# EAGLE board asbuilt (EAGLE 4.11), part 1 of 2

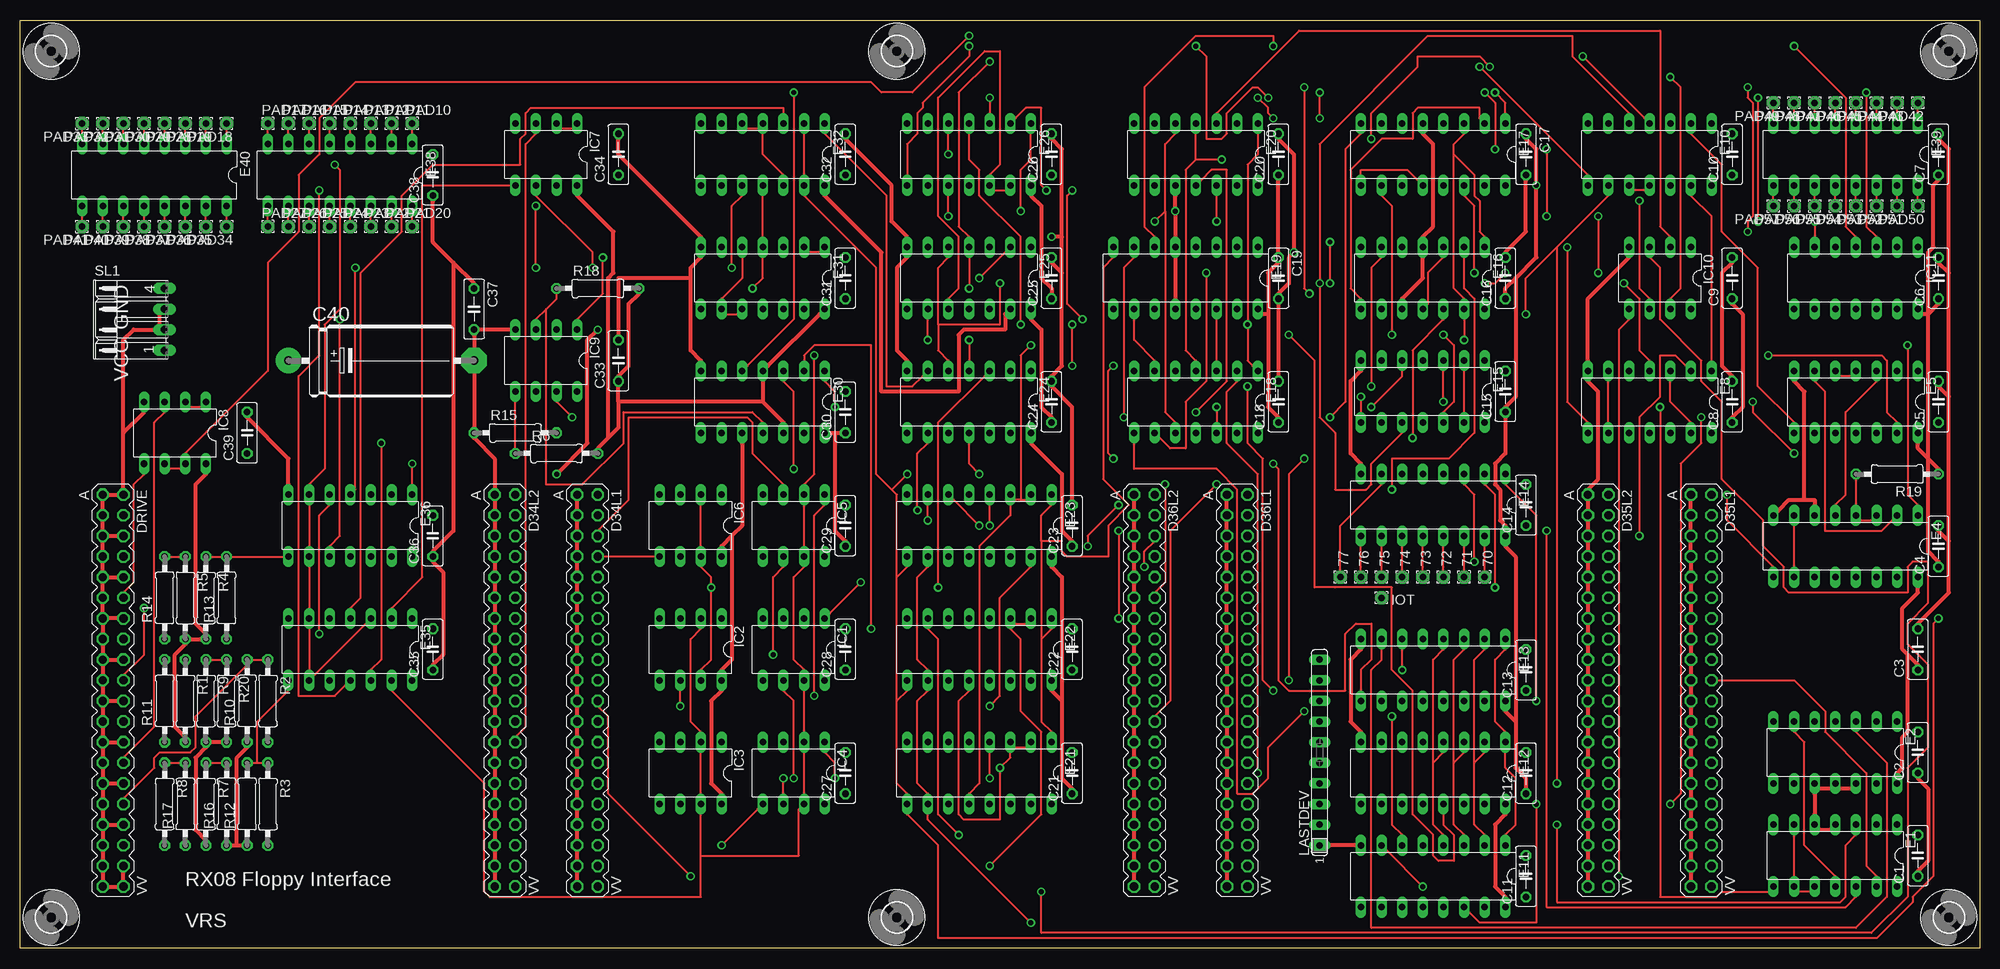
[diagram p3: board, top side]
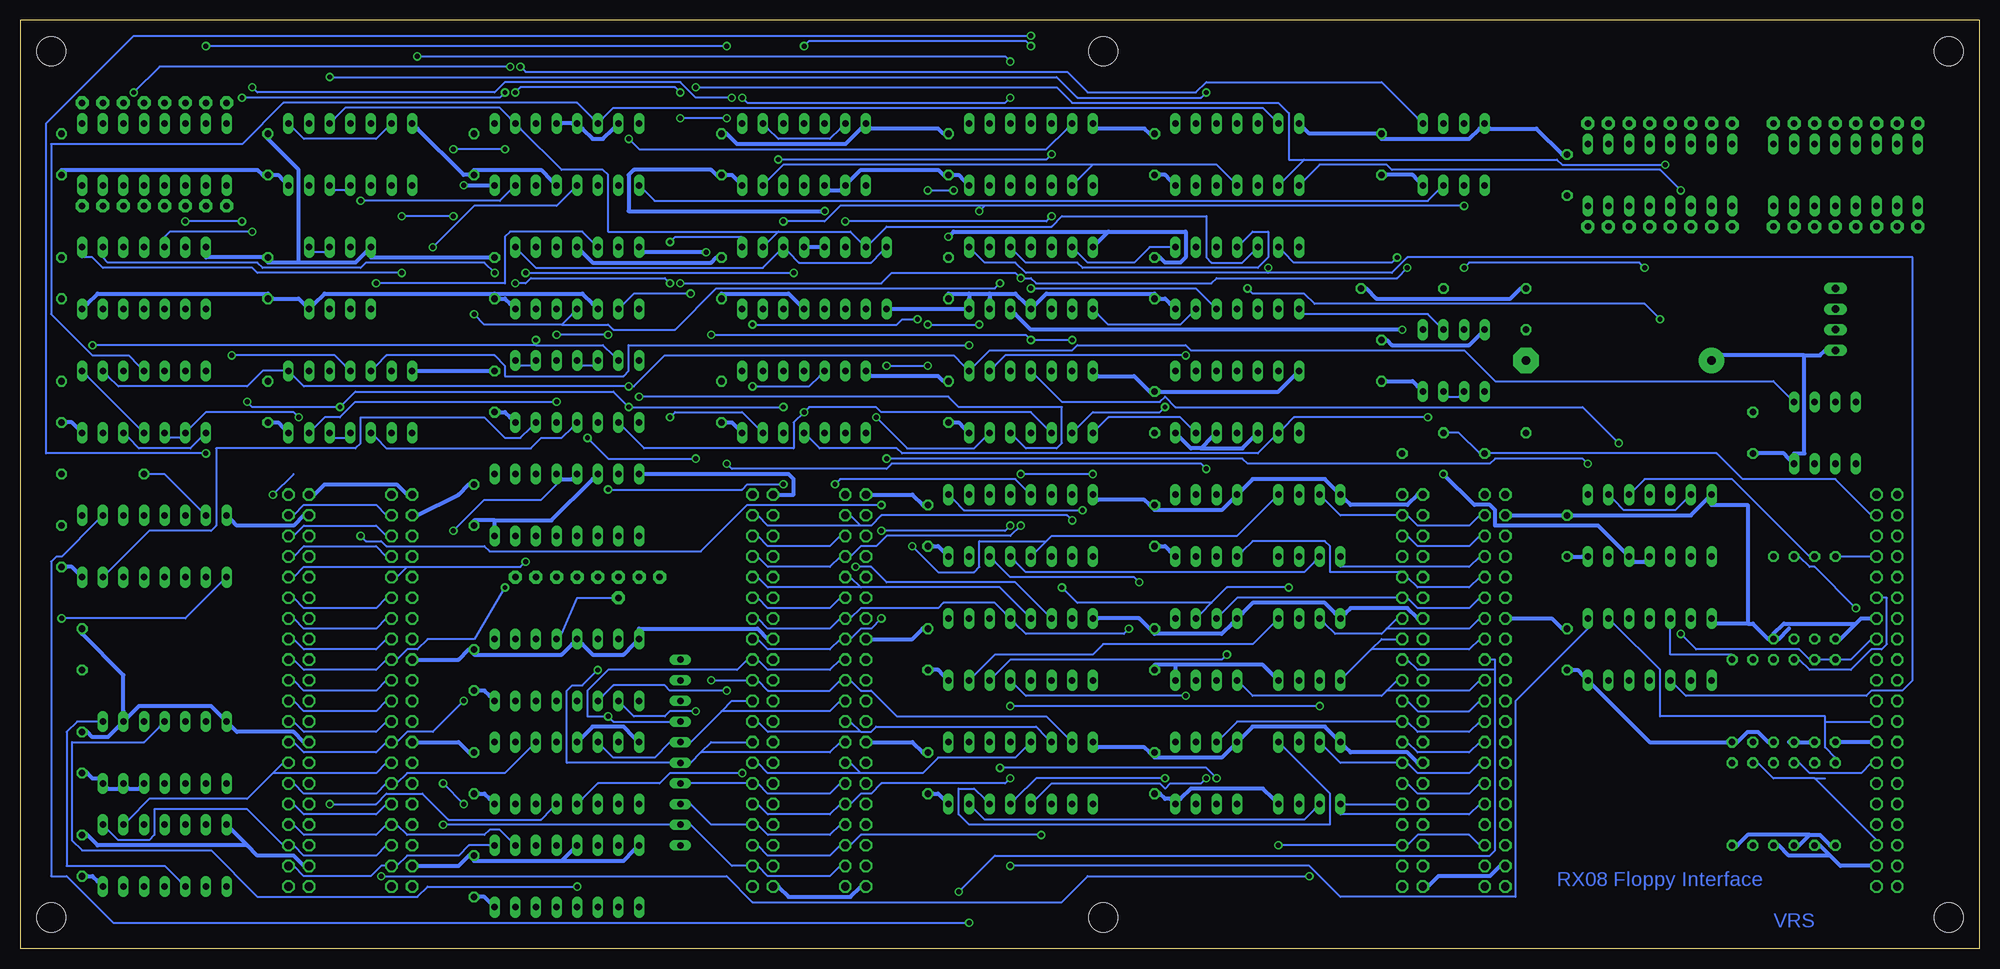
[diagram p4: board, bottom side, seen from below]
Size 241.3 x 114.3 mm. Coordinates in mm from the lower left corner, seen from the top.
Outline: 0,0 0,114.3 241.3,114.3 241.3,0 0,0
Copper layers (1*16): Top 0.035mm / dielectric 1.5mm / Bottom 0.035mm
Design rules "olimex10mil": minimum track width 10mil, minimum drill 24mil, track to track 10mil, track to pad 10mil, pad to pad 10mil, via to via 10mil, smd to smd 10mil, copper to edge 25mil, drill to drill 10mil, minimum pad ring 10mil, minimum via ring 8mil, stop-mask expansion 0mil, vias tented up to drill 0mil, thermal gap 10mil
Net classes: 1 supply: width 0.508 mm

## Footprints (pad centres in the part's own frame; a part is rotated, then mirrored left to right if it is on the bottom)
1,6/0,8 = drill 0.813 pad 1.6 octagon: 1 0,0
C050-025X075 = drill 0.813 octagon: 1 -2.54,0; 2 2.54,0
E22-9 = drill 1.016 pad 3.15 round: + -11.43,0 | drill 1.016 pad 3.15 octagon: - 11.43,0
DEC40PIN = drill 1.016 octagon: A -24.13,-1.27; AA 3.81,-1.27; B -24.13,1.27; BB 3.81,1.27; C -21.59,-1.27; CC 6.35,-1.27; D -21.59,1.27; DD 6.35,1.27; E -19.05,-1.27; EE 8.89,-1.27; F -19.05,1.27; FF 8.89,1.27; H -16.51,-1.27; HH 11.43,-1.27; J -16.51,1.27; JJ 11.43,1.27; K -13.97,-1.27; KK 13.97,-1.27; L -13.97,1.27; LL 13.97,1.27; M -11.43,-1.27; MM 16.51,-1.27; N -11.43,1.27; NN 16.51,1.27; P -8.89,-1.27; PP 19.05,-1.27; R -8.89,1.27; RR 19.05,1.27; S -6.35,-1.27; SS 21.59,-1.27; T -6.35,1.27; TT 21.59,1.27; U -3.81,-1.27; UU 24.13,-1.27; V -3.81,1.27; VV 24.13,1.27; W -1.27,-1.27; X -1.27,1.27; Y 1.27,-1.27; Z 1.27,1.27
DIL14 = drill 0.813 long: 1 -7.62,-3.81; 2 -5.08,-3.81; 3 -2.54,-3.81; 4 0,-3.81; 5 2.54,-3.81; 6 5.08,-3.81; 7 7.62,-3.81; 8 7.62,3.81; 9 5.08,3.81; 10 2.54,3.81; 11 0,3.81; 12 -2.54,3.81; 13 -5.08,3.81; 14 -7.62,3.81
DIL16 = drill 0.813 long: 1 -8.89,-3.81; 2 -6.35,-3.81; 3 -3.81,-3.81; 4 -1.27,-3.81; 5 1.27,-3.81; 6 3.81,-3.81; 7 6.35,-3.81; 8 8.89,-3.81; 9 8.89,3.81; 10 6.35,3.81; 11 3.81,3.81; 12 1.27,3.81; 13 -1.27,3.81; 14 -3.81,3.81; 15 -6.35,3.81; 16 -8.89,3.81
DIL08 = drill 0.813 long: 1 -3.81,-3.81; 2 -1.27,-3.81; 3 1.27,-3.81; 4 3.81,-3.81; 5 3.81,3.81; 6 1.27,3.81; 7 -1.27,3.81; 8 -3.81,3.81
SIL10 = drill 0.813 long: 1 -11.43,0; 2 -8.89,0; 3 -6.35,0; 4 -3.81,0; 5 -1.27,0; 6 1.27,0; 7 3.81,0; 8 6.35,0; 9 8.89,0; 10 11.43,0
0207/10 = drill 0.813 octagon: 1 -5.08,0; 2 5.08,0
04PA = drill 0.914 long: 1 -3.81,0; 2 -1.27,0; 3 1.27,0; 4 3.81,0
3,6 = hole 3.6: 0,0

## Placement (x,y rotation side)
70  [1,6/0,8]  180.34,45.72 270 top
71  [1,6/0,8]  177.8,45.72 270 top
72  [1,6/0,8]  175.26,45.72 270 top
73  [1,6/0,8]  172.72,45.72 270 top
74  [1,6/0,8]  170.18,45.72 270 top
75  [1,6/0,8]  167.64,45.72 270 top
76  [1,6/0,8]  165.1,45.72 270 top
77  [1,6/0,8]  162.56,45.72 270 top
C1  0.1  [C050-025X075]  233.68,11.43 90 top
C2  0.1  [C050-025X075]  233.68,24.13 90 top
C3  0.1  [C050-025X075]  233.68,36.83 90 top
C4  0.1  [C050-025X075]  236.22,49.53 90 top
C5  0.1  [C050-025X075]  236.22,67.31 90 top
C6  0.1  [C050-025X075]  236.22,82.55 90 top
C7  0.1  [C050-025X075]  236.22,97.79 90 top
C8  0.1  [C050-025X075]  210.82,67.31 90 top
C9  0.1  [C050-025X075]  210.82,82.55 90 top
C10  0.1  [C050-025X075]  210.82,97.79 90 top
C11  0.1  [C050-025X075]  185.42,8.89 90 top
C12  0.1  [C050-025X075]  185.42,21.59 90 top
C13  0.1  [C050-025X075]  185.42,34.29 90 top
C14  0.1  [C050-025X075]  185.42,54.61 90 top
C15  0.1  [C050-025X075]  182.88,68.58 90 top
C16  0.1  [C050-025X075]  182.88,82.55 90 top
C17  0.1  [C050-025X075]  185.42,97.79 270 top
C18  0.1  [C050-025X075]  154.94,67.31 90 top
C19  0.1  [C050-025X075]  154.94,82.55 270 top
C20  0.1  [C050-025X075]  154.94,97.79 90 top
C21  0.1  [C050-025X075]  129.54,21.59 90 top
C22  0.1  [C050-025X075]  129.54,36.83 90 top
C23  0.1  [C050-025X075]  129.54,52.07 90 top
C24  0.1  [C050-025X075]  127,67.31 90 top
C25  0.1  [C050-025X075]  127,82.55 90 top
C26  0.1  [C050-025X075]  127,97.79 90 top
C27  0.1  [C050-025X075]  101.6,21.59 90 top
C28  0.1  [C050-025X075]  101.6,36.83 90 top
C29  0.1  [C050-025X075]  101.6,52.07 90 top
C30  0.1  [C050-025X075]  101.6,66.04 90 top
C31  0.1  [C050-025X075]  101.6,82.55 90 top
C32  0.1  [C050-025X075]  101.6,97.79 90 top
C33  0.1  [C050-025X075]  73.66,72.39 90 top
C34  0.1  [C050-025X075]  73.66,97.79 90 top
C35  0.1  [C050-025X075]  50.8,36.83 90 top
C36  0.1  [C050-025X075]  50.8,50.8 90 top
C37  0.1  [C050-025X075]  55.88,78.74 270 top
C38  0.1  [C050-025X075]  50.8,95.25 90 top
C39  0.1  [C050-025X075]  27.94,63.5 90 top
C40  100uf  [E22-9]  44.45,72.39 0 top
D34L1  [DEC40PIN]  69.85,31.75 270 top
D34L2  [DEC40PIN]  59.69,31.75 270 top
D35L1  [DEC40PIN]  207.01,31.75 270 top
D35L2  [DEC40PIN]  194.31,31.75 270 top
D36L1  [DEC40PIN]  149.86,31.75 270 top
D36L2  [DEC40PIN]  138.43,31.75 270 top
DRIVE  [DEC40PIN]  11.43,31.75 270 top
E1  74LS10N  [DIL14]  223.52,11.43 180 top
E2  74LS74N  [DIL14]  223.52,24.13 180 top
E4  74LS161N  [DIL16]  224.79,49.53 180 top
E5  74LS00N  [DIL14]  226.06,67.31 180 top
E8  74LS10N  [DIL14]  200.66,67.31 180 top
E10  74LS10N  [DIL14]  200.66,97.79 180 top
E11  74LS138N  [DIL16]  173.99,8.89 180 top
E12  74LS138N  [DIL16]  173.99,21.59 180 top
E13  74LS138N  [DIL16]  173.99,34.29 180 top
E14  74LS138N  [DIL16]  173.99,54.61 180 top
E15  74LS00N  [DIL14]  172.72,68.58 180 top
E16  74LS74N  [DIL14]  172.72,82.55 180 top
E17  74LS76N  [DIL16]  173.99,97.79 180 top
E18  74LS02N  [DIL14]  144.78,67.31 180 top
E19  74LS76N  [DIL16]  143.51,82.55 180 top
E20  74HCT32N  [DIL14]  144.78,97.79 180 top
E21  74LS195N  [DIL16]  118.11,21.59 180 top
E22  74LS195N  [DIL16]  118.11,36.83 180 top
E23  74LS195N  [DIL16]  118.11,52.07 180 top
E24  74LS08N  [DIL14]  116.84,67.31 180 top
E25  74LS04N  [DIL14]  116.84,82.55 180 top
E26  74LS86N  [DIL14]  116.84,97.79 180 top
E30  74LS74N  [DIL14]  91.44,67.31 180 top
E31  74LS20N  [DIL14]  91.44,82.55 180 top
E32  74LS27N  [DIL14]  91.44,97.79 180 top
E35  74HCT02N  [DIL14]  40.64,36.83 180 top
E36  74HCT02N  [DIL14]  40.64,52.07 180 top
E38  SPARE  [DIL16]  39.37,95.25 180 top
E39  SPARE  [DIL16]  224.79,97.79 180 top
E40  SPARE  [DIL16]  16.51,95.25 180 top
IC1  DS75452N  [DIL08]  95.25,36.83 180 top
IC2  DS75452N  [DIL08]  82.55,36.83 180 top
IC3  DS75452N  [DIL08]  82.55,21.59 180 top
IC4  DS75452N  [DIL08]  95.25,21.59 180 top
IC5  DS75452N  [DIL08]  95.25,52.07 180 top
IC6  DS75452N  [DIL08]  82.55,52.07 180 top
IC7  DS75452N  [DIL08]  64.77,97.79 180 top
IC8  DS75452N  [DIL08]  19.05,63.5 180 top
IC9  DS75452N  [DIL08]  64.77,72.39 180 top
IC10  DS75452N  [DIL08]  201.93,82.55 180 top
IC11  74LS04N  [DIL14]  226.06,82.55 180 top
IOT  [1,6/0,8]  167.64,43.18 270 top
LASTDEV  100  [SIL10]  160.02,24.13 90 top
PAD10  [1,6/0,8]  48.26,101.6 0 top
PAD11  [1,6/0,8]  45.72,101.6 0 top
PAD12  [1,6/0,8]  43.18,101.6 0 top
PAD13  [1,6/0,8]  40.64,101.6 0 top
PAD14  [1,6/0,8]  38.1,101.6 0 top
PAD15  [1,6/0,8]  35.56,101.6 0 top
PAD16  [1,6/0,8]  33.02,101.6 0 top
PAD17  [1,6/0,8]  30.48,101.6 0 top
PAD18  [1,6/0,8]  25.4,101.6 180 top
PAD19  [1,6/0,8]  22.86,101.6 180 top
PAD20  [1,6/0,8]  48.26,88.9 0 top
PAD21  [1,6/0,8]  45.72,88.9 0 top
PAD22  [1,6/0,8]  43.18,88.9 0 top
PAD23  [1,6/0,8]  40.64,88.9 0 top
PAD24  [1,6/0,8]  38.1,88.9 0 top
PAD25  [1,6/0,8]  35.56,88.9 0 top
PAD26  [1,6/0,8]  33.02,88.9 0 top
PAD27  [1,6/0,8]  30.48,88.9 0 top
PAD28  [1,6/0,8]  20.32,101.6 180 top
PAD29  [1,6/0,8]  17.78,101.6 180 top
PAD30  [1,6/0,8]  15.24,101.6 180 top
PAD31  [1,6/0,8]  12.7,101.6 180 top
PAD32  [1,6/0,8]  10.16,101.6 180 top
PAD33  [1,6/0,8]  7.62,101.6 180 top
PAD34  [1,6/0,8]  25.4,88.9 180 top
PAD35  [1,6/0,8]  22.86,88.9 180 top
PAD36  [1,6/0,8]  20.32,88.9 180 top
PAD37  [1,6/0,8]  17.78,88.9 180 top
PAD38  [1,6/0,8]  15.24,88.9 180 top
PAD39  [1,6/0,8]  12.7,88.9 180 top
PAD40  [1,6/0,8]  10.16,88.9 180 top
PAD41  [1,6/0,8]  7.62,88.9 180 top
PAD42  [1,6/0,8]  233.68,104.14 180 top
PAD43  [1,6/0,8]  231.14,104.14 180 top
PAD44  [1,6/0,8]  228.6,104.14 180 top
PAD45  [1,6/0,8]  226.06,104.14 180 top
PAD46  [1,6/0,8]  223.52,104.14 180 top
PAD47  [1,6/0,8]  220.98,104.14 180 top
PAD48  [1,6/0,8]  218.44,104.14 180 top
PAD49  [1,6/0,8]  215.9,104.14 180 top
PAD50  [1,6/0,8]  233.68,91.44 180 top
PAD51  [1,6/0,8]  231.14,91.44 180 top
PAD52  [1,6/0,8]  228.6,91.44 180 top
PAD53  [1,6/0,8]  226.06,91.44 180 top
PAD54  [1,6/0,8]  223.52,91.44 180 top
PAD55  [1,6/0,8]  220.98,91.44 180 top
PAD56  [1,6/0,8]  218.44,91.44 180 top
PAD57  [1,6/0,8]  215.9,91.44 180 top
R1  180  [0207/10]  20.32,30.48 270 top
R2  180  [0207/10]  30.48,30.48 270 top
R3  180  [0207/10]  30.48,17.78 270 top
R4  180  [0207/10]  22.86,43.18 270 top
R5  180  [0207/10]  20.32,43.18 270 top
R6  180  [0207/10]  66.04,60.96 0 top
R7  180  [0207/10]  22.86,17.78 270 top
R8  180  [0207/10]  17.78,17.78 270 top
R9  390  [0207/10]  22.86,30.48 270 top
R10  390  [0207/10]  27.94,30.48 90 top
R11  390  [0207/10]  17.78,30.48 90 top
R12  390  [0207/10]  27.94,17.78 90 top
R13  390  [0207/10]  25.4,43.18 90 top
R14  390  [0207/10]  17.78,43.18 90 top
R15  390  [0207/10]  60.96,63.5 0 top
R16  390  [0207/10]  25.4,17.78 90 top
R17  390  [0207/10]  20.32,17.78 90 top
R18  10K  [0207/10]  71.12,81.28 0 top
R19  10K  [0207/10]  231.14,58.42 180 top
R20  180  [0207/10]  25.4,30.48 270 top
SL1  [04PA]  17.78,77.47 90 top
U$1  [3,6]  237.49,3.81 0 top
U$2  [3,6]  237.49,110.49 0 top
U$3  [3,6]  3.81,110.49 0 top
U$4  [3,6]  3.81,3.81 0 top
U$5  [3,6]  107.95,110.49 0 top
U$6  [3,6]  107.95,3.81 0 top

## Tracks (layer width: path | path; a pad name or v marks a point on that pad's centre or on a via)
8/12  (via drill 0.61)
  Top 0.254: v197.49,81.92 199.39,80.01 199.39,73.66 200.66,72.39 E8.4 | v215.26,73.03 229.24,73.03 229.87,72.39 229.87,66.04 231.14,64.77 E5.13
  Bottom 0.254: v197.49,81.92 181.61,81.92 181.61,87.63 180.97,88.27 172.09,88.27 170.81,87 E16.5 | v215.26,73.03 202.56,73.03 201.29,71.75 E8.4
8/12\  (via drill 0.61)
  Top 0.254: v166.37,69.22 166.37,83.82 167.64,85.09 E16.6 | E10.13 205.74,92.71 208.28,90.17 208.28,72.39 E8.1 | IC8.2 20.95,66.67 22.23,66.67 IC8.1
  Bottom 0.254: E5.2 230.5,70.48 229.24,69.22 213.36,69.22 211.46,71.12 208.91,71.12 E8.1 207.65,70.48 206.38,69.22 v166.37,69.22 165.74,69.22 161.93,73.03 126.36,73.03 125.09,71.75 E24.1 123.83,71.75 121.92,73.66 111.76,73.66 111.12,74.3 97.79,74.3 97.16,73.66 63.5,73.66 59.69,69.85 25.4,69.85 23.5,67.94 IC8.1
ACB00\
  Bottom 0.254: IC6.3 80.64,55.24 78.74,53.34 71.75,53.34 D34L1.D 70.48,53.34 69.22,52.07 62.87,52.07 61.59,53.34 D34L2.D
ACB01\
  Top 0.254: IC6.5 78.11,48.26 71.75,48.26 D34L1.J
  Bottom 0.254: D34L2.J 61.59,48.26 62.87,46.99 78.74,46.99 IC6.5
ACB02\
  Bottom 0.254: IC1.3 93.34,41.27 91.44,43.18 71.75,43.18 D34L1.N 70.48,43.18 69.22,41.91 62.87,41.91 61.59,43.18 D34L2.N
ACB03\
  Bottom 0.254: 74.93,36.83 73.66,38.1 71.75,38.1 D34L1.T | 74.93,36.83 78.11,33.66 IC2.5 | 74.93,36.83 62.87,36.83 61.59,38.1 D34L2.T
ACB04\
  Bottom 0.254: 73.03,31.75 71.75,33.02 D34L1.X | 73.03,31.75 73.66,31.11 89.53,31.11 90.81,32.38 IC1.5 | 73.03,31.75 62.87,31.75 61.59,33.02 D34L2.X
ACB05\
  Bottom 0.254: IC4.3 93.34,26.04 91.44,27.94 71.75,27.94 D34L1.BB 70.48,27.94 69.22,26.67 62.87,26.67 61.59,27.94 D34L2.BB
ACB06\
  Bottom 0.254: IC3.3 80.64,24.77 78.74,22.86 71.75,22.86 D34L1.FF 70.48,22.86 69.22,21.59 62.87,21.59 61.59,22.86 D34L2.FF
ACB07\
  Bottom 0.254: D34L1.LL 71.75,17.78 78.11,17.78 IC3.5 78.74,16.51 62.87,16.51 61.59,17.78 D34L2.LL
ACB08\  (via drill 0.61)
  Top 0.254: v86.36,12.7 90.81,17.14 IC4.5
  Bottom 0.254: v86.36,12.7 71.75,12.7 D34L1.RR 70.48,12.7 69.22,13.97 62.87,13.97 61.59,12.7 D34L2.RR
ACB09\
  Top 0.254: IC5.3 93.98,57.15 90.17,60.96 90.17,64.77 89.53,65.41 74.93,65.41 74.93,55.24 71.12,51.44 D34L1.F
  Bottom 0.254: D34L2.F 61.59,50.8 62.87,49.53 69.22,49.53 70.48,50.8 D34L1.F
ACB10\
  Bottom 0.254: IC5.5 90.81,48.9 89.53,50.16 80.64,50.16 80.01,49.53 80.01,46.35 71.12,46.35 D34L1.L 70.48,45.72 69.22,44.45 62.87,44.45 61.59,45.72 D34L2.L
ACB11\
  Bottom 0.254: 73.03,39.37 71.75,40.64 D34L1.R | 73.03,39.37 73.66,38.73 79.38,38.73 80.64,40.01 IC2.3 | 73.03,39.37 62.87,39.37 61.59,40.64 D34L2.R
ACCLEAR\
  Top 0.254: IC7.3 63.5,100.33 62.23,99.06 62.23,27.3 60.96,26.04 D34L2.DD
  Bottom 0.254: D34L1.DD 70.48,25.4 69.22,24.13 62.87,24.13 61.59,25.4 D34L2.DD
BAC00  (via drill 0.61)
  Top 0.254: v111.76,52.7 111.76,54.61 E23.7
  Bottom 0.254: v111.76,52.7 112.39,53.34 135.25,53.34 136.53,52.07 137.79,52.07 | 137.79,52.07 139.06,53.34 D36L2.D | 137.79,52.07 149.22,52.07 150.5,53.34 D36L1.D
BAC01  (via drill 0.61)
  Top 0.254: v118.11,52.07 114.94,55.24 E23.6
  Bottom 0.254: v118.11,52.07 119.38,50.8 134.62,50.8 135.89,49.53 137.79,49.53 139.06,48.26 D36L2.J 140.34,48.26 141.6,46.99 149.22,46.99 150.5,48.26 D36L1.J
BAC02  (via drill 0.61)
  Top 0.254: v140.97,57.15 140.97,45.09 139.7,43.81 D36L2.N
  Bottom 0.254: v140.97,57.15 140.34,57.78 118.75,57.78 117.47,56.52 E23.5 | D36L1.N 150.5,43.18 149.22,41.91 141.6,41.91 140.34,43.18 D36L2.N
BAC03  (via drill 0.61)
  Top 0.254: v119.38,52.07 119.38,54.61 E23.4 | v135.25,51.44 v135.25,40.64
  Bottom 0.254: v119.38,52.07 120.02,51.44 v135.25,51.44 | v135.25,40.64 136.53,39.37 137.79,39.37 139.06,38.1 D36L2.T 140.34,38.1 141.6,36.83 149.22,36.83 150.5,38.1 D36L1.T
BAC04  (via drill 0.61)
  Top 0.254: v171.45,62.87 171.45,73.66 175.26,77.47 E16.12 | v158.12,60.33 156.21,58.42 v156.21,33.02
  Bottom 0.254: E21.7 112.39,26.04 114.94,28.57 133.35,28.57 136.53,31.75 137.79,31.75 139.06,33.02 D36L2.X 140.34,33.02 141.6,31.75 149.22,31.75 150.5,33.02 D36L1.X 151.76,33.02 v156.21,33.02 | v171.45,62.87 168.91,60.33 v158.12,60.33
BAC05  (via drill 0.61)
  Top 0.254: v168.91,56.52 168.91,60.33 175.9,60.33 179.07,63.5 179.07,80.01 177.8,81.28 177.8,85.09 E16.2 | v147.32,57.15 141.6,51.44 141.6,30.48 139.7,28.57 D36L2.BB
  Bottom 0.254: 137.79,26.67 136.53,26.67 135.89,27.3 116.2,27.3 114.94,26.04 E21.6 | 137.79,26.67 139.06,27.94 D36L2.BB | 137.79,26.67 149.22,26.67 150.5,27.94 D36L1.BB | v168.91,56.52 152.4,56.52 151.76,57.15 v147.32,57.15
BAC06
  Bottom 0.254: 137.79,21.59 130.18,21.59 128.27,23.5 118.75,23.5 117.47,24.77 E21.5 | 137.79,21.59 139.06,22.86 D36L2.FF | 137.79,21.59 149.22,21.59 150.5,22.86 D36L1.FF
BAC07  (via drill 0.61)
  Top 0.254: v119.38,20.95 119.38,24.13 E21.4
  Bottom 0.254: v119.38,20.95 120.02,20.32 135.25,20.32 136.53,19.05 137.79,19.05 139.06,17.78 D36L2.LL 140.34,17.78 141.6,16.51 149.22,16.51 150.5,17.78 D36L1.LL
BAC08  (via drill 0.61)
  Top 0.254: v115.57,13.97 113.03,16.51 113.03,38.1 111.76,39.37 E22.7
  Bottom 0.254: v115.57,13.97 137.79,13.97 139.06,12.7 D36L2.RR 140.34,12.7 141.6,11.43 149.22,11.43 150.5,12.7 D36L1.RR
BAC09  (via drill 0.61)
  Top 0.254: v138.43,46.99 138.43,48.9 139.7,50.16 D36L2.F
  Bottom 0.254: v138.43,46.99 136.53,46.99 134.62,45.09 118.75,45.09 114.94,41.27 E22.6 | D36L1.F 150.5,50.8 149.22,49.53 141.6,49.53 140.34,50.8 D36L2.F
BAC10
  Bottom 0.254: 137.79,44.45 120.65,44.45 117.47,41.27 E22.5 | 137.79,44.45 139.06,45.72 D36L2.L | 137.79,44.45 149.22,44.45 150.5,45.72 D36L1.L
BAC11  (via drill 0.61)
  Top 0.254: v104.78,39.37 104.78,74.3 97.79,74.3 96.52,73.03 96.52,72.39 E30.2
  Bottom 0.254: D36L1.R 150.5,40.64 149.22,39.37 141.6,39.37 140.34,40.64 D36L2.R 139.06,40.64 137.79,41.91 128.27,41.91 127.64,42.55 121.28,42.55 120.02,41.27 E22.4 118.75,40.01 117.47,38.73 105.41,38.73 v104.78,39.37
BINIT  (via drill 0.61)
  Top 0.254: v189.23,15.24 189.23,5.71 224.16,5.71 224.79,6.35 224.79,12.7 226.06,13.97 E1.3
  Bottom 0.254: v189.23,15.24 161.29,15.24 LASTDEV.2 158.75,15.24 153.67,10.16 151.76,10.16 D36L1.TT 150.5,10.16 149.22,8.89 141.6,8.89 140.34,10.16 D36L2.TT
BIOP1  (via drill 0.61)
  Top 0.254: v168.91,28.57 168.91,15.24 170.18,13.97 E11.6
  Bottom 0.254: D36L2.V 140.34,35.56 141.6,34.29 149.22,34.29 150.5,35.56 D36L1.V 151.76,35.56 153.03,34.29 168.91,34.29 171.45,31.75 171.45,28.57 v168.91,28.57 168.28,27.94 161.29,27.94 LASTDEV.7
BIOP2
  Bottom 0.254: 154.94,29.21 153.67,30.48 151.76,30.48 D36L1.Z | 154.94,29.21 158.75,25.4 LASTDEV.6 161.29,25.4 163.19,23.5 168.28,23.5 169.54,24.77 E12.6 | 154.94,29.21 141.6,29.21 140.34,30.48 D36L2.Z
BIOP4  (via drill 0.61)
  Top 0.254: v170.18,34.29 170.18,36.83 E13.6
  Bottom 0.254: 157.48,24.13 156.21,25.4 151.76,25.4 D36L1.DD | 157.48,24.13 158.75,22.86 LASTDEV.5 161.29,22.86 173.99,22.86 173.99,31.75 173.35,32.38 172.09,32.38 v170.18,34.29 | 157.48,24.13 141.6,24.13 140.34,25.4 D36L2.DD
BMB00
  Bottom 0.254: D35L2.D 196.22,53.34 197.49,54.61 206.38,54.61 207.65,53.34 D35L1.D
BMB01
  Bottom 0.254: D35L2.J 196.22,48.26 197.49,49.53 206.38,49.53 207.65,48.26 D35L1.J
BMB02
  Bottom 0.254: D35L2.N 196.22,43.18 197.49,41.91 206.38,41.91 207.65,43.18 D35L1.N
BMB03
  Top 0.254: E1.13 228.6,8.89 227.33,10.16 227.33,21.59 222.25,26.67 222.25,29.21 218.44,33.02 208.91,33.02 D35L1.X
  Bottom 0.254: D35L2.X 196.22,33.02 197.49,31.75 206.38,31.75 207.65,33.02 D35L1.X
BMB03\
  Bottom 0.254: D35L2.T 196.22,38.1 197.49,36.83 206.38,36.83 207.65,38.1 D35L1.T
BMB04
  Bottom 0.254: 210.19,21.59 208.91,22.86 D35L1.FF | 210.19,21.59 213.36,18.41 225.43,18.41 227.97,15.88 E1.2 | 210.19,21.59 197.49,21.59 196.22,22.86 D35L2.FF
BMB04\
  Bottom 0.254: D35L2.BB 196.22,27.94 197.49,26.67 206.38,26.67 207.65,27.94 D35L1.BB
BMB05
  Bottom 0.254: E1.1 230.5,14.61 229.24,13.34 225.43,13.34 224.79,13.97 224.79,17.14 213.36,17.14 208.91,12.7 D35L1.RR 207.65,12.7 206.38,11.43 197.49,11.43 196.22,12.7 D35L2.RR
BMB05\
  Bottom 0.254: D35L2.LL 196.22,17.78 197.49,16.51 206.38,16.51 207.65,17.78 D35L1.LL
BMB06  (via drill 0.61)
  Top 0.254: v179.07,47.62 179.07,55.88 177.8,57.15 E14.3
  Bottom 0.254: v179.07,47.62 179.71,46.99 193.68,46.99 | 193.68,46.99 194.94,45.72 D35L2.L | 193.68,46.99 206.38,46.99 207.65,45.72 D35L1.L
BMB06\
  Bottom 0.254: D35L2.F 196.22,50.8 197.49,52.07 206.38,52.07 207.65,50.8 D35L1.F
BMB07  (via drill 0.61)
  Top 0.254: v181.61,44.45 181.61,55.88 180.34,57.15 E14.2
  Bottom 0.254: D35L1.V 207.65,35.56 206.38,34.29 197.49,34.29 196.22,35.56 D35L2.V 194.94,35.56 193.68,36.83 192.41,36.83 191.13,38.1 185.42,38.1 v181.61,44.45
BMB07\
  Bottom 0.254: D35L2.R 196.22,40.64 197.49,39.37 206.38,39.37 207.65,40.64 D35L1.R
BMB08  (via drill 0.61)
  Top 0.254: v186.69,30.48 186.69,53.34 182.88,57.15 E14.1
  Bottom 0.254: v186.69,30.48 190.5,26.67 193.68,26.67 194.94,25.4 D35L2.DD 196.22,25.4 197.49,24.13 206.38,24.13 207.65,25.4 D35L1.DD
BMB08\
  Bottom 0.254: D35L2.Z 196.22,30.48 197.49,29.21 206.38,29.21 207.65,30.48 D35L1.Z
BMB09
  Top 0.254: 176.53,22.86 176.53,15.24 177.8,13.97 E11.3 | 176.53,22.86 177.8,24.13 E12.3 | 176.53,22.86 176.53,35.56 177.8,36.83 E13.3
  Bottom 0.254: D35L1.JJ 207.65,20.32 206.38,19.05 197.49,19.05 196.22,20.32 D35L2.JJ 194.94,20.32 193.68,21.59 181.61,21.59 178.44,24.77 E12.3
BMB10
  Top 0.254: 179.07,22.86 179.07,15.24 180.34,13.97 E11.2 | 179.07,22.86 180.34,24.13 E12.2 | 179.07,22.86 179.07,35.56 180.34,36.83 E13.2
  Bottom 0.254: D35L1.NN 207.65,15.24 206.38,13.97 197.49,13.97 196.22,15.24 D35L2.NN 194.94,15.24 193.68,13.97 184.15,13.97 183.51,14.61 182.25,14.61 180.97,13.34 E11.2
BMB11
  Top 0.254: E11.1 182.88,13.97 184.15,15.24 184.15,20.95 182.88,22.23 182.88,24.13 E12.1 182.88,26.67 181.61,27.94 181.61,35.56 182.88,36.83 E13.1
  Bottom 0.254: E11.1 183.51,12.7 186.06,12.7 187.32,11.43 193.68,11.43 194.94,10.16 D35L2.TT 196.22,10.16 196.85,10.16 198.12,8.89 206.38,8.89 207.65,10.16 D35L1.TT
BRUN\
  Bottom 0.254: D34L2.JJ 61.59,20.32 62.87,19.05 69.22,19.05 70.48,20.32 D34L1.JJ
BTS1
  Bottom 0.254: LASTDEV.3 158.75,17.78 156.21,15.24 151.76,15.24 D36L1.NN 150.5,15.24 149.22,13.97 141.6,13.97 140.34,15.24 D36L2.NN
BTS3
  Bottom 0.254: LASTDEV.4 158.75,20.32 151.76,20.32 D36L1.JJ 150.5,20.32 149.22,19.05 141.6,19.05 140.34,20.32 D36L2.JJ
CLK_BUF  (via drill 0.61)
  Top 0.254: E4.2 230.5,52.7 229.24,51.44 222.25,51.44 222.25,68.58 220.98,69.85 E5.6 | E23.10 111.76,46.99 110.49,45.72 110.49,35.56 111.76,34.29 E22.10 111.76,31.75 110.49,30.48 110.49,20.32 111.76,19.05 E21.10 111.76,16.51 111.76,15.88 v124.46,3.17
  Bottom 0.254: v124.46,3.17 229.87,3.17 235.59,8.89 237.49,8.89 237.49,47.62 236.85,48.26 236.22,48.26 231.78,52.7 E4.2
CLK_PARITY\
  Top 0.254: E5.5 224.16,70.48 225.43,70.48 E5.4
  Bottom 0.254: E32.6 87,102.23 88.27,103.5 168.28,103.5 169.54,102.23 E17.6 170.81,102.23 172.72,104.14 208.91,104.14 214,99.06 237.49,99.06 237.49,78.11 232.41,73.03 227.97,73.03 226.69,71.75 E5.4
DONE  (via drill 0.61)
  Top 0.254: v39.37,77.47 39.37,50.8 38.1,49.53 E36.10 | E32.11 91.44,92.71 91.44,87.63 E31.4 91.44,85.09 91.44,82.55 v90.17,81.28
  Bottom 0.254: v39.37,77.47 41.27,79.38 81.92,79.38 83.19,80.64 87,80.64 89.53,80.64 v90.17,81.28 | 109.22,96.52 111.12,94.61 E26.9 | 109.22,96.52 93.98,96.52 92.08,94.61 E32.11 | E25.3 118.75,85.72 117.47,84.45 111.12,84.45 110.49,83.82 88.9,83.82 87.63,85.09 87.63,88.27 89.53,88.27 90.81,87 E31.4 | 109.22,96.52 147.32,96.52 149.22,94.61 E20.13
DONE\  (via drill 0.61)
  Top 0.254: v116.84,81.28 116.84,85.09 E25.4 116.84,87.63 115.57,88.9 115.57,105.41 v119.38,109.22 | v192.41,109.86 200.03,102.23 E10.4
  Bottom 0.254: v116.84,81.28 96.52,81.28 94.61,79.38 E31.12 | v192.41,109.86 120.02,109.86 v119.38,109.22
DONE_FF  (via drill 0.61)
  Top 0.254: v199.39,92.08 199.39,81.28 200.66,80.01 IC10.6
  Bottom 0.254: v199.39,92.08 182.25,92.08 180.97,93.34 E17.15
DONE_SKIP  (via drill 0.61)
  Top 0.254: v114.3,90.17 114.3,92.71 E26.10 | v139.7,89.53 140.97,90.81 | 140.97,90.81 140.97,99.06 142.24,100.33 E20.5 | 140.97,90.81 140.97,66.04 142.24,64.77 E18.10
  Bottom 0.254: v114.3,90.17 114.94,89.53 v139.7,89.53
ENB_BUF_LD\  (via drill 0.61)
  Top 0.254: E32.2 96.52,100.33 96.52,95.25 E32.13 96.52,92.71 105.41,83.82 105.41,58.42 107.31,56.52 | 107.95,30.48 107.95,20.32 109.22,19.05 E21.9 109.22,16.51 113.03,12.7 113.03,1.27 228.6,1.27 233.04,5.71 233.04,6.35 235.59,8.89 235.59,40.01 v236.22,40.64 | 107.95,30.48 109.22,31.75 E22.9 | 107.95,45.72 109.22,46.99 E23.9 | 107.95,30.48 107.95,45.72 | 107.31,56.52 107.95,55.88 107.95,45.72 | v210.19,55.88 210.19,52.7 215.9,46.99 E4.9 | v118.11,58.42 116.84,59.69 116.84,62.23 E24.11 | 107.31,56.52 v109.22,58.42
  Bottom 0.254: v210.19,55.88 207.65,58.42 | v109.22,58.42 v118.11,58.42 | v236.22,40.64 220.98,40.64 216.53,45.09 E4.9
ERR_SKIP  (via drill 0.61)
  Top 0.254: v114.3,97.79 114.3,100.33 E26.5 | v147.96,97.16 144.78,97.16 | 144.78,97.16 144.78,100.33 E20.4 | 144.78,97.16 143.51,95.89 143.51,73.66 144.78,72.39 E18.4
  Bottom 0.254: v114.3,97.79 114.94,97.16 v147.96,97.16
ERROR  (via drill 0.61)
  Top 0.254: v48.26,59.69 48.26,57.15 E36.1 | v134.62,60.33 133.99,60.96 133.99,71.12 v134.62,71.75 | v129.54,71.75 v129.54,76.83 | v123.19,76.83 123.19,87.63 118.11,92.71 118.11,95.89 116.84,97.16 116.84,100.33 E26.4
  Bottom 0.254: v48.26,59.69 48.9,60.33 59.69,60.33 60.33,59.69 90.17,59.69 90.81,60.33 v134.62,60.33 | v134.62,71.75 v129.54,71.75 | v129.54,76.83 v123.19,76.83
GND  (via drill 0.61)
  Top 0.508: 26.67,12.7 27.3,12.7 R12.1 | 26.67,12.7 26.04,12.7 R16.1 | 26.67,12.7 26.67,23.5 27.94,24.77 R10.1 | C34.2 73.66,99.69 73.66,97.79 83.82,87.63 E31.7 83.82,85.09 82.55,83.82 82.55,82.55 | C32.2 101.6,99.69 107.31,93.98 107.31,89.53 109.22,87.63 E25.7 109.22,85.09 107.95,83.82 107.95,73.66 109.22,72.39 E24.7 | 82.55,82.55 82.55,73.66 83.82,72.39 E30.7 | D34L1.A 68.58,55.24 68.58,53.98 D34L1.C 68.58,52.7 68.58,51.44 D34L1.E 68.58,50.16 68.58,48.9 D34L1.H 68.58,47.62 68.58,46.35 D34L1.K 68.58,45.09 68.58,43.81 D34L1.M 68.58,42.55 68.58,41.27 D34L1.P 68.58,40.01 68.58,38.73 D34L1.S 68.58,37.47 68.58,36.2 D34L1.U 68.58,34.92 68.58,33.66 D34L1.W 68.58,32.38 68.58,31.11 D34L1.Y 68.58,29.84 68.58,28.57 D34L1.AA 68.58,27.3 68.58,26.04 D34L1.CC 68.58,24.77 68.58,23.5 D34L1.EE 68.58,22.23 68.58,20.95 D34L1.HH 68.58,19.68 68.58,18.41 D34L1.KK 68.58,17.14 68.58,15.88 D34L1.MM 68.58,14.61 68.58,13.34 D34L1.PP 68.58,12.06 68.58,10.79 D34L1.SS 68.58,9.53 68.58,8.26 D34L1.UU | IC9.4 60.33,76.2 56.52,76.2 C37.2 55.88,75.56 55.88,73.66 C40.- 55.88,71.12 55.88,64.14 R15.1 55.88,62.87 58.42,60.33 58.42,56.52 D34L2.A 58.42,55.24 58.42,53.98 D34L2.C 58.42,52.7 58.42,51.44 D34L2.E 58.42,50.16 58.42,48.9 D34L2.H 58.42,47.62 58.42,46.35 D34L2.K 58.42,45.09 58.42,43.81 D34L2.M 58.42,42.55 58.42,41.27 D34L2.P 58.42,40.01 58.42,38.73 D34L2.S 58.42,37.47 58.42,36.2 D34L2.U 58.42,34.92 58.42,33.66 D34L2.W 58.42,32.38 58.42,31.11 D34L2.Y 58.42,29.84 58.42,28.57 D34L2.AA 58.42,27.3 58.42,26.04 D34L2.CC 58.42,24.77 58.42,23.5 D34L2.EE 58.42,22.23 58.42,20.95 D34L2.HH 58.42,19.68 58.42,18.41 D34L2.KK 58.42,17.14 58.42,15.88 D34L2.MM 58.42,14.61 58.42,13.34 D34L2.PP 58.42,12.06 58.42,10.79 D34L2.SS 58.42,9.53 58.42,8.26 D34L2.UU
  Top 0.508: 82.55,82.55 73.66,82.55 73.66,75.56 C33.2 | C18.2 154.94,70.48 154.94,79.38 C19.2 154.94,80.64 156.21,81.92 156.21,85.09 v156.84,85.72 156.84,97.79 154.94,99.69 C20.2 | 128.27,83.19 127,84.45 C25.2 | 128.27,83.19 128.27,71.75 127,70.48 C24.2 127,69.22 129.54,66.67 129.54,55.24 C23.2 | 128.27,83.19 128.27,87.63 | 128.27,87.63 128.27,98.42 127,99.69 C26.2 | D36L2.A 137.16,55.24 137.16,53.98 D36L2.C 137.16,52.7 137.16,51.44 D36L2.E 137.16,50.16 137.16,48.9 D36L2.H 137.16,47.62 137.16,46.35 D36L2.K 137.16,45.09 137.16,43.81 D36L2.M 137.16,42.55 137.16,41.27 D36L2.P 137.16,40.01 137.16,38.73 D36L2.S 137.16,37.47 137.16,36.2 D36L2.U 137.16,34.92 137.16,33.66 D36L2.W 137.16,32.38 137.16,31.11 D36L2.Y 137.16,29.84 137.16,28.57 D36L2.AA 137.16,27.3 137.16,26.04 D36L2.CC 137.16,24.77 137.16,23.5 D36L2.EE 137.16,22.23 137.16,20.95 D36L2.HH 137.16,19.68 137.16,18.41 D36L2.KK 137.16,17.14 137.16,15.88 D36L2.MM 137.16,14.61 137.16,13.34 D36L2.PP 137.16,12.06 137.16,10.79 D36L2.SS 137.16,9.53 137.16,8.26 D36L2.UU | 237.49,50.16 236.22,51.44 C4.2 | 237.49,50.16 237.49,43.81 233.68,40.01 C3.2 | 237.49,67.94 236.22,69.22 C5.2 | 237.49,50.16 237.49,67.94 | 237.49,83.19 236.22,84.45 C6.2 | 237.49,67.94 237.49,83.19 | 237.49,83.19 237.49,98.42 236.22,99.69 C7.2 | 219.71,55.24 220.98,55.24 220.98,54.61 E4.6 | 219.71,55.24 217.81,55.24 216.53,53.98 E4.8 | 219.71,55.24 219.71,68.58 218.44,69.85 E5.7 | D35L1.UU 205.74,8.26 205.74,9.53 D35L1.SS 205.74,10.79 205.74,12.06 D35L1.PP 205.74,13.34 205.74,14.61 D35L1.MM 205.74,15.88 205.74,17.14 D35L1.KK 205.74,18.41 205.74,19.68 D35L1.HH 205.74,20.95 205.74,22.23 D35L1.EE 205.74,23.5 205.74,24.77 D35L1.CC 205.74,26.04 205.74,27.3 D35L1.AA 205.74,28.57 205.74,29.84 D35L1.Y 205.74,31.11 205.74,32.38 D35L1.W 205.74,33.66 205.74,34.92 D35L1.U 205.74,36.2 205.74,37.47 D35L1.S 205.74,38.73 205.74,40.01 D35L1.P 205.74,41.27 205.74,42.55 D35L1.M 205.74,43.81 205.74,45.09 D35L1.K 205.74,46.35 205.74,47.62 D35L1.H 205.74,48.9 205.74,50.16 D35L1.E 205.74,51.44 205.74,52.7 D35L1.C 205.74,53.98 205.74,55.24 D35L1.A
  Top 0.508: D36L1.UU 148.59,8.26 148.59,9.53 D36L1.SS 148.59,10.79 148.59,12.06 D36L1.PP 148.59,13.34 148.59,14.61 D36L1.MM 148.59,15.88 148.59,17.14 D36L1.KK 148.59,18.41 148.59,19.68 D36L1.HH 148.59,20.95 148.59,22.23 D36L1.EE 148.59,23.5 148.59,24.77 D36L1.CC 148.59,26.04 148.59,27.3 D36L1.AA 148.59,28.57 148.59,29.84 D36L1.Y 148.59,31.11 148.59,32.38 D36L1.W 148.59,33.66 148.59,34.92 D36L1.U 148.59,36.2 148.59,37.47 D36L1.S 148.59,38.73 148.59,40.01 D36L1.P 148.59,41.27 148.59,42.55 D36L1.M 148.59,43.81 148.59,45.09 D36L1.K 148.59,46.35 148.59,47.62 D36L1.H 148.59,48.9 148.59,50.16 D36L1.E 148.59,51.44 148.59,52.7 D36L1.C 148.59,53.98 148.59,55.24 D36L1.A | C16.2 182.88,85.72 185.42,88.27 185.42,94.61 C17.2 | C8.2 210.82,70.48 209.55,71.75 209.55,83.19 210.82,84.45 C9.2 | LASTDEV.1 161.29,12.7 164.47,12.7 E11.8 | D35L2.UU 193.04,8.26 193.04,9.53 D35L2.SS 193.04,10.79 193.04,12.06 D35L2.PP 193.04,13.34 193.04,14.61 D35L2.MM 193.04,15.88 193.04,17.14 D35L2.KK 193.04,18.41 193.04,19.68 D35L2.HH 193.04,20.95 193.04,22.23 D35L2.EE 193.04,23.5 193.04,24.77 D35L2.CC 193.04,26.04 193.04,27.3 D35L2.AA 193.04,28.57 193.04,29.84 D35L2.Y 193.04,31.11 193.04,32.38 D35L2.W 193.04,33.66 193.04,34.92 D35L2.U 193.04,36.2 193.04,37.47 D35L2.S 193.04,38.73 193.04,40.01 D35L2.P 193.04,41.27 193.04,42.55 D35L2.M 193.04,43.81 193.04,45.09 D35L2.K 193.04,46.35 193.04,47.62 D35L2.H 193.04,48.9 193.04,50.16 D35L2.E 193.04,51.44 193.04,52.7 D35L2.C 193.04,53.98 193.04,55.24 D35L2.A 193.04,56.52 194.31,57.78 194.31,68.58 193.04,69.85 E8.7 193.04,72.39 193.04,80.01 198.12,85.09 IC10.4
  Top 0.508: E12.8 165.1,26.67 163.83,27.94 163.83,35.56 165.1,36.83 E13.8 | 12.7,63.5 15.24,66.04 IC8.4 | 12.7,63.5 12.7,56.52 DRIVE.B 12.06,55.88 10.79,55.88 DRIVE.A 10.16,55.24 10.16,53.98 DRIVE.C 10.16,52.7 10.16,51.44 DRIVE.E | 12.7,63.5 12.7,74.93 13.97,76.2 SL1.2 17.14,76.83 17.14,78.11 SL1.3 | C39.2 27.94,65.41 33.02,60.33 33.02,57.15 E36.7 | DRIVE.TT 12.7,9.53 12.7,8.26 DRIVE.VV 12.06,7.62 10.79,7.62 DRIVE.UU 10.16,8.26 10.16,9.53 DRIVE.SS 10.16,10.79 10.16,12.06 DRIVE.PP 10.16,13.34 10.16,14.61 DRIVE.MM | DRIVE.NN 12.06,15.24 10.79,15.24 DRIVE.MM | DRIVE.MM 10.16,15.88 10.16,17.14 DRIVE.KK 10.16,18.41 10.16,19.68 DRIVE.HH | DRIVE.JJ 12.06,20.32 10.79,20.32 DRIVE.HH | DRIVE.HH 10.16,20.95 10.16,22.23 DRIVE.EE 10.16,23.5 10.16,24.77 DRIVE.CC | DRIVE.CC 10.16,26.04 10.16,27.3 DRIVE.AA 10.16,28.57 10.16,29.84 DRIVE.Y | DRIVE.Z 12.06,30.48 10.79,30.48 DRIVE.Y | DRIVE.Y 10.16,31.11 10.16,32.38 DRIVE.W 10.16,33.66 10.16,34.92 DRIVE.U | DRIVE.V 12.06,35.56 10.79,35.56 DRIVE.U | DRIVE.U 10.16,36.2 10.16,37.47 DRIVE.S 10.16,38.73 10.16,40.01 DRIVE.P | DRIVE.P 10.16,41.27 10.16,42.55 DRIVE.M 10.16,43.81 10.16,45.09 DRIVE.K | DRIVE.L 12.06,45.72 10.79,45.72 DRIVE.K | DRIVE.K 10.16,46.35 10.16,47.62 DRIVE.H 10.16,48.9 10.16,50.16 DRIVE.E | DRIVE.F 12.06,50.8 10.79,50.8 DRIVE.E | DRIVE.DD 12.06,25.4 10.79,25.4 DRIVE.CC | DRIVE.R 12.06,40.64 10.79,40.64 DRIVE.P | 128.27,87.63 v127,87.63 | E14.8 165.1,59.69 163.83,60.96 163.83,69.85 165.1,71.12 E15.7
  Bottom 0.508: 28.57,40.01 32.38,40.01 E35.7 | 28.57,40.01 27.94,40.01 26.04,38.1 R13.1 | 17.14,38.1 R14.1 17.14,38.1 | 23.5,39.37 24.77,38.1 R13.1 | 18.41,11.43 17.14,10.16 13.34,10.16 DRIVE.TT | 18.41,11.43 19.68,12.7 R17.1 | 17.14,25.4 R11.1 17.14,25.4 | 18.41,11.43 23.5,11.43 24.77,12.7 R16.1 | C38.2 51.44,97.79 54.61,100.97 60.33,100.97 IC7.4 61.59,100.97 62.87,99.69 73.66,99.69 C34.2 74.3,100.33 82.55,100.33 83.19,100.97 E32.7 | C32.2 102.23,100.33 102.87,100.97 108.58,100.97 E26.7 | 107.31,88.27 97.79,88.27 97.79,85.09 98.42,84.45 100.33,84.45 100.97,85.09 C31.2 | 107.31,88.27 108.58,87 E25.7 | E24.7 108.58,70.48 104.14,70.48 102.23,68.58 C30.2 100.97,68.58 86.36,68.58 84.45,70.48 E30.7 | E23.8 108.58,55.24 102.87,55.24 102.23,54.61 C29.2 101.6,53.98 93.34,53.98 92.08,55.24 IC5.4 90.81,56.52 89.53,57.78 80.64,57.78 79.38,56.52 IC6.4 78.11,55.24 77.47,54.61 70.48,54.61 69.22,55.88 D34L1.A | E22.8 108.58,40.64 103.5,40.64 102.23,39.37 C28.2 101.6,38.73 93.34,38.73 92.08,40.01 IC1.4 90.81,41.27 89.53,42.55 80.64,42.55 79.38,41.27 IC2.4 78.11,41.27 77.47,41.91 70.48,41.91 69.22,40.64 D34L1.P | E21.8 108.58,24.77 102.87,24.77 102.23,24.13 C27.2 101.6,23.5 93.34,23.5 92.08,24.77 IC4.4 90.81,26.04 89.53,27.3 80.64,27.3 79.38,26.04 IC3.4 78.11,24.77 77.47,24.13 70.48,24.13 69.22,22.86 D34L1.EE | C33.2 73.03,74.93 72.39,74.3 62.87,74.3 61.59,75.56 IC9.4 | C35.2 51.44,39.37 52.7,40.64 57.78,40.64 D34L2.P | D34L2.C 57.78,53.34 51.44,53.34 C36.2 50.16,53.34 35.56,53.34 33.66,55.24 E36.7 33.02,54.61 28.57,54.61 28.57,40.01 | D34L1.UU 67.94,7.62 66.67,8.89 60.33,8.89 59.05,10.16 D34L2.SS
  Bottom 0.508: E19.13 145.41,79.38 146.69,80.64 154.94,80.64 C19.2 | v156.84,85.72 164.47,85.72 E16.7 | C26.2 127.64,100.33 128.27,100.97 136.53,100.97 E20.7 137.79,100.97 139.7,99.06 153.03,99.06 154.31,100.33 C20.2 | C24.2 127.64,69.85 128.27,70.48 136.53,70.48 E18.7 | C23.2 130.18,54.61 131.44,55.88 136.53,55.88 D36L2.A | C22.2 130.18,39.37 131.44,38.1 136.53,38.1 D36L2.S | C21.2 130.18,24.13 131.44,25.4 136.53,25.4 D36L2.CC | C2.2 233.04,26.67 232.41,26.04 230.5,26.04 229.24,27.3 E2.2 | C3.2 233.68,38.73 228.6,33.66 228.6,29.21 E2.2 | D35L1.CC 206.38,25.4 207.65,26.67 214.63,26.67 215.26,27.3 E2.7 216.53,28.57 217.81,29.84 226.69,29.84 227.97,28.57 E2.2 | 213.36,12.7 212.09,11.43 207.65,11.43 206.38,10.16 D35L1.SS | 213.36,12.7 215.26,14.61 E1.7 | E4.8 215.26,52.7 214.63,52.07 207.65,52.07 206.38,53.34 D35L1.C | E17.13 175.9,94.61 177.16,95.89 185.42,95.89 C17.2 186.06,95.25 186.69,95.25 192.41,100.97 E10.7 | 207.01,84.45 210.82,84.45 C9.2 211.46,85.09 218.44,85.09 IC11.7 | 207.01,84.45 200.03,84.45 198.75,85.72 IC10.4 198.12,85.09 183.51,85.09 C16.2 | 207.01,84.45 207.01,95.89 210.82,99.69 C10.2 | D35L2.SS 192.41,10.16 187.32,10.16 186.06,11.43 C11.2 185.42,10.79 174.62,10.79 | 174.62,10.79 173.35,12.06 E11.5 | 174.62,10.79 167,10.79 165.74,12.06 E11.8 | C15.2 183.51,71.12 192.41,71.12 E8.7 | C14.2 186.06,57.15 187.32,55.88 192.41,53.34 D35L2.C | E12.8 165.74,26.04 167,27.3 170.81,27.3 172.09,26.04 E12.5 | C12.2 186.06,24.13 187.32,25.4 192.41,25.4 D35L2.CC | D35L2.U 192.41,35.56 187.32,35.56 186.06,36.83 C13.2 185.42,36.2 174.62,36.2 173.35,37.47 E13.5 172.09,37.47 170.81,36.2 167,36.2 165.74,37.47 E13.8 165.1,39.37 150.5,39.37 149.22,38.1 D36L1.S
  Bottom 0.508: D35L1.A 205.1,55.88 203.84,57.15 194.94,57.15 193.68,55.88 D35L2.A | D36L2.UU 137.79,7.62 139.06,6.35 146.69,6.35 147.96,7.62 D36L1.UU | 213.36,12.7 231.78,12.7 233.04,13.97 C1.2 | 15.24,40.01 14.61,40.64 13.34,40.64 DRIVE.R | 15.24,40.01 17.14,38.1 | 17.14,25.4 13.34,25.4 DRIVE.DD | 15.24,40.01 24.13,40.01 25.4,38.73 R13.1 | v127,87.63 126.36,88.27 107.31,88.27 | E14.8 164.47,58.42 146.69,58.42 146.05,57.78 146.05,55.88 147.96,55.88 D36L1.A
INIT  (via drill 0.61)
  Top 0.254: v147.32,66.67 147.32,64.77 E18.12 | v166.37,66.67 170.18,70.48 170.18,71.12 E15.5 | v201.93,66.67 201.93,6.35 208.91,6.35 209.55,6.99 215.26,6.99 E1.8 | IC8.6 18.41,59.05 19.68,59.05 IC8.7 20.32,60.96 30.48,71.12 30.48,84.45 34.29,88.27 34.29,95.25 36.83,97.79 36.83,102.23 41.27,106.68 104.78,106.68 106.05,105.41 109.86,105.41 v116.84,112.39 | v218.44,60.96 213.36,66.04 v213.36,67.31
  Bottom 0.254: v147.32,66.67 v166.37,66.67 168.28,68.58 200.03,68.58 v201.93,66.67 212.72,66.67 v213.36,67.31 | E15.4 172.09,71.75 170.81,71.75 E15.5 | v116.84,112.39 227.33,112.39 238.12,101.6 238.12,60.96 v218.44,60.96
INIT1\  (via drill 0.61)
  Top 0.254: v172.72,7.62 168.28,12.06 E11.7
  Bottom 0.254: v172.72,7.62 191.13,7.62 192.41,6.35 212.09,6.35 217.81,12.06 233.68,12.06 234.95,13.34 234.95,25.4 226.06,25.4 224.16,27.3 E2.4
INIT4\
  Top 0.254: E2.3 226.06,26.67 229.87,22.86 229.87,6.35 226.06,2.54 166.37,2.54 166.37,34.29 167.64,35.56 167.64,36.83 E13.7
INIT\  (via drill 0.61)
  Top 0.254: v100.33,66.67 100.33,68.58 99.06,69.85 E30.1 | 125.73,38.1 125.73,27.94 127,26.67 E21.1 | 125.73,38.1 127,39.37 E22.1 | 125.73,50.16 125.73,38.1 | 125.73,50.16 125.73,53.34 127,54.61 E23.1 | v110.49,53.98 110.49,60.96 111.76,62.23 E24.9 | 176.53,97.79 176.53,99.06 177.8,100.33 E17.3 | 176.53,97.79 176.53,81.28 177.8,80.01 E16.13 177.8,77.47 v177.8,74.93 | 176.53,97.79 179.07,95.25 179.07,92.71 179.71,92.08 179.71,88.27 180.34,87.63 E16.1 | v232.41,74.3 232.41,55.88 233.68,54.61 E4.1 | 125.73,50.16 128.27,50.16 128.27,48.9 128.91,48.26 133.99,48.26 133.99,52.07 136.53,54.61 133.35,57.78 133.35,83.82 134.62,85.09 E19.8
  Bottom 0.254: v100.33,66.67 100.97,66.04 109.22,66.04 111.12,64.14 E24.9 | v110.49,53.98 125.09,53.98 126.36,55.24 E23.1 | E19.8 135.25,85.72 136.53,84.45 145.41,84.45 146.69,85.72 E19.3 147.96,85.72 149.86,83.82 177.8,83.82 179.71,85.72 E16.1 | 177.8,74.3 169.54,74.3 168.28,73.03 E15.6 | 177.8,74.3 v232.41,74.3 | v177.8,74.93 177.8,74.3
INT_RQ\  (via drill 0.61)
  Top 0.254: v196.85,8.89 196.85,76.2 198.12,77.47 IC10.5 | v82.55,8.89 72.39,19.05 72.39,28.57 71.12,29.84 D34L1.Z
  Bottom 0.254: v196.85,8.89 154.31,8.89 151.13,5.71 113.03,5.71 109.86,8.89 v82.55,8.89 | D34L2.Z 61.59,30.48 62.87,29.21 69.22,29.21 70.48,30.48 D34L1.Z
INTR4\  (via drill 0.61)
  Top 0.254: v95.25,59.05 95.25,68.58 93.98,69.85 E30.3 | v154.31,59.69 154.94,59.05 154.94,33.02 156.21,31.75 163.19,31.75 163.19,38.73 164.47,40.01 166.37,40.01 166.37,35.56 165.1,34.29 165.1,31.75 E13.9
  Bottom 0.254: v95.25,59.05 95.89,59.69 133.99,59.69 134.62,59.05 153.67,59.05 v154.31,59.69
IOS\  (via drill 0.61)
  Top 0.254: v125.73,6.99 125.73,1.91 227.97,1.91 232.41,6.35 232.41,22.23 234.95,24.77 234.95,34.92 232.41,37.47 232.41,40.01 234.95,42.55 234.95,47.62 233.04,47.62 232.41,46.99 232.41,43.81 217.81,43.81 217.17,44.45 217.17,46.99 214.63,49.53 214.63,52.7 209.55,57.78 209.55,67.31 207.01,69.85 207.01,72.39 201.93,77.47 201.93,83.82 200.66,85.09 IC10.3
  Bottom 0.254: v125.73,6.99 121.28,11.43 60.33,11.43 59.69,12.06 59.69,34.29 | 59.69,34.29 59.69,35.56 60.33,35.56 D34L2.V | 59.69,34.29 69.22,34.29 70.48,35.56 D34L1.V
LCD1
  Top 0.254: E31.2 97.16,85.72 98.42,85.72 E31.1
  Bottom 0.254: E25.6 111.12,85.72 109.86,84.45 104.14,84.45 102.23,86.36 99.69,86.36 E31.1
LCD1\  (via drill 0.61)
  Top 0.254: 113.03,76.83 113.03,83.82 114.3,85.09 E25.5 | 113.03,76.83 113.03,73.66 114.3,72.39 E24.5 | E16.3 175.26,85.09 173.35,83.19 173.35,79.38 E16.11 | 189.23,86.36 185.42,82.55 v185.42,78.11 | 189.23,86.36 195.58,92.71 E10.9 | 113.03,76.83 120.65,76.83 v120.65,81.92 | v186.69,17.78 186.69,3.17 179.71,3.17 178.44,4.45 E11.14 | 189.23,86.36 v189.23,20.32
  Bottom 0.254: v185.42,78.11 184.15,76.83 174.62,76.83 | 174.62,76.83 173.35,78.11 E16.11 | v120.65,81.92 121.28,81.28 155.57,81.28 160.66,76.2 168.28,76.2 168.91,76.83 174.62,76.83 | v189.23,20.32 v186.69,17.78
MAINT  (via drill 0.61)
  Top 0.254: E35.3 42.55,40.01 36.2,33.66 E35.9 35.56,34.29 35.56,39.37 E35.6 35.56,41.91 35.56,46.99 E36.9 35.56,49.53 35.56,54.61 E36.6 35.56,57.15 37.47,59.05 37.47,76.83 39.37,78.74 39.37,95.89 v38.73,96.52 | v158.75,80.64 158.12,81.28 v158.12,106.05
  Bottom 0.254: E36.2 45.09,55.24 43.81,53.98 37.47,53.98 36.2,55.24 E36.6 | 83.19,97.16 85.72,94.61 E32.9 | 83.19,97.16 52.07,97.16 51.44,96.52 v38.73,96.52 | v158.75,80.64 165.74,80.64 167,79.38 E16.9 | v158.12,106.05 113.67,106.05 111.76,104.14 86.36,104.14 85.09,102.87 85.09,97.16 83.19,97.16
MAINT\  (via drill 0.61)
  Top 0.254: E16.8 165.1,80.01 163.83,81.28 163.83,95.89 167.64,99.69 171.45,99.69 171.45,102.87 172.09,103.5 179.71,103.5 179.71,102.23 E17.2 | E31.5 88.9,85.09 88.9,82.55 86.36,80.01 E31.9 87,78.11 88.27,78.11 E31.10 | v135.89,65.41 135.89,83.82 137.16,85.09 E19.7
  Bottom 0.254: E10.3 202.56,102.23 201.29,103.5 182.25,103.5 180.97,102.23 E17.2 179.71,100.97 174.62,95.89 169.54,95.89 168.91,95.25 168.91,88.27 147.96,88.27 | v135.89,65.41 132.08,61.59 123.83,61.59 122.56,62.87 E24.13 | 147.96,88.27 149.22,87 E19.2 | 147.96,88.27 139.06,88.27 137.79,87 E19.7 136.53,87 134.62,88.9 114.3,88.9 113.03,90.17 95.25,90.17 95.25,85.09 94.61,84.45 90.81,84.45 89.53,85.72 E31.5
MSB8  (via drill 0.61)
  Top 0.254: E21.12 116.84,19.05 118.11,20.32 118.11,49.53 121.92,53.34 121.92,54.61 E23.3 122.56,55.24 123.19,55.24 | v95.25,20.95 95.25,30.48 93.98,31.75 IC1.6 | 123.19,55.24 123.83,55.24 E23.2 | v124.46,74.3 123.19,73.03 123.19,55.24
  Bottom 0.254: v95.25,20.95 95.89,20.32 99.69,20.32 100.33,19.68 100.97,20.32 114.3,20.32 116.2,18.41 E21.12 | v124.46,74.3 166.37,74.3 166.37,71.12 167,70.48 181.61,70.48 181.61,71.75 182.88,73.03 196.22,73.03 197.49,71.75 E8.5
MSB12  (via drill 0.61)
  Top 0.254: v199.39,50.8 199.39,65.41 201.93,67.94 201.93,73.03 203.84,73.03 205.1,71.75 E8.2 | v135.25,54.61 131.44,50.8 v131.44,49.53
  Bottom 0.254: 114.94,50.16 116.2,48.9 E23.12 | 114.94,50.16 114.3,50.8 91.44,50.8 87,55.24 IC6.1 | v199.39,50.8 198.75,50.16 196.85,50.16 196.22,49.53 184.15,49.53 183.51,48.9 157.48,48.9 151.76,54.61 v135.25,54.61 | v131.44,49.53 128.27,46.35 123.83,46.35 123.19,46.99 123.19,50.16 114.94,50.16
MYDEV\
  Top 0.254: 173.99,22.86 173.99,15.24 175.26,13.97 E11.4 | 173.99,22.86 175.26,24.13 E12.4 | 173.99,22.86 173.99,35.56 175.26,36.83 E13.4
  Bottom 0.254: E13.4 174.62,38.73 172.72,43.18 168.28,43.18 IOT.1
N$1
  Top 0.254: E14.9 165.1,46.99 165.1,46.35 76.1
N$2  (via drill 0.61)
  Top 0.254: v103.5,45.09 99.69,41.27 IC1.1
  Bottom 0.254: v103.5,45.09 104.14,45.72 119.38,45.72 121.28,47.62 E23.14
N$3  (via drill 0.61)
  Top 0.254: 83.82,11.43 83.82,16.51 IC3.7 83.82,19.05 83.82,24.13 IC3.2 83.82,26.67 82.55,27.94 82.55,38.1 83.82,39.37 IC2.2 | 83.82,11.43 83.82,6.35 57.78,6.35 57.15,6.99 57.15,20.32 45.72,31.75 E35.13 | v97.79,73.03 97.79,58.42 96.52,57.15 IC5.2 96.52,54.61 96.52,49.53 IC5.7 96.52,46.99 95.25,45.72 95.25,35.56 96.52,34.29 IC1.7 96.52,31.75 96.52,26.67 IC4.2 96.52,24.13 96.52,19.05 IC4.7 95.89,17.14 95.89,11.43 83.82,11.43
  Bottom 0.254: v97.79,73.03 120.02,73.03 121.28,71.75 E24.2
N$4  (via drill 0.61)
  Top 0.254: v36.83,93.34 36.83,73.03 34.29,70.48 34.29,31.11 38.73,31.11 40.01,32.38 E35.11
  Bottom 0.254: v36.83,93.34 39.37,95.89 72.39,95.89 73.03,96.52 81.28,96.52 83.19,94.61 E32.8
N$5
  Top 0.254: E14.15 180.34,46.99 180.34,46.35 70.1
N$6
  Top 0.254: E14.14 177.8,46.99 177.8,46.35 71.1
N$7
  Top 0.254: E14.13 175.26,46.99 175.26,46.35 72.1
N$8
  Top 0.254: E14.12 172.72,46.99 172.72,46.35 73.1
N$9
  Top 0.254: E14.11 170.18,46.99 170.18,46.35 74.1
N$10
  Top 0.254: E14.10 167.64,46.99 167.64,46.35 75.1
N$11
  Top 0.254: E14.7 167.64,57.15 162.56,52.07 162.56,46.35 77.1
N$12  (via drill 0.61)
  Top 0.254: IC2.7 83.82,34.29 85.09,35.56 v85.09,44.45 85.09,45.72 83.82,46.99 IC6.7 83.82,49.53 83.82,54.61 IC6.2 | v113.03,44.45 113.03,64.77 118.75,70.48 E24.3
  Bottom 0.254: 94.61,42.55 92.71,44.45 v85.09,44.45 | 94.61,42.55 95.89,41.27 IC1.2 | v113.03,44.45 111.12,42.55 94.61,42.55
N$13
  Top 0.254: E38.1 48.26,100.33 48.26,100.97 PAD10.1
N$14
  Top 0.254: E38.2 45.72,100.33 45.72,100.97 PAD11.1
N$15
  Top 0.254: E38.3 43.18,100.33 43.18,100.97 PAD12.1
N$16
  Top 0.254: E38.4 40.64,100.33 40.64,100.97 PAD13.1
N$17
  Top 0.254: E38.5 38.1,100.33 38.1,100.97 PAD14.1
N$18
  Top 0.254: E38.6 35.56,100.33 35.56,100.97 PAD15.1
N$19
  Top 0.254: E38.7 33.02,100.33 33.02,100.97 PAD16.1
N$20
  Top 0.254: E38.8 30.48,100.33 30.48,100.97 PAD17.1
N$21
  Top 0.254: E4.5 223.52,54.61 224.79,55.88 224.79,66.04 228.6,69.85 E5.3
N$22  (via drill 0.61)
  Top 0.254: v144.78,66.04 148.59,69.85 148.59,95.89 146.69,95.89 145.41,94.61 E20.11
  Bottom 0.254: E24.10 114.94,64.14 116.84,66.04 135.25,66.04 135.89,66.67 144.15,66.67 v144.78,66.04 146.05,64.77 146.05,61.59 164.47,61.59 167,64.14 E15.9
N$23
  Top 0.254: E38.16 48.26,90.17 48.26,89.53 PAD20.1
N$24
  Top 0.254: E38.15 45.72,90.17 45.72,89.53 PAD21.1
N$25
  Top 0.254: E38.14 43.18,90.17 43.18,89.53 PAD22.1
N$26
  Top 0.254: E38.13 40.64,90.17 40.64,89.53 PAD23.1
N$27
  Top 0.254: E38.12 38.1,90.17 38.1,89.53 PAD24.1
N$28
  Top 0.254: E38.11 35.56,90.17 35.56,89.53 PAD25.1
N$29
  Top 0.254: E38.10 33.02,90.17 33.02,89.53 PAD26.1
N$30
  Top 0.254: E38.9 30.48,90.17 30.48,89.53 PAD27.1
N$31  (via drill 0.61)
  Top 0.254: v93.98,20.95 93.98,19.05 IC4.6 | E21.2 123.83,24.77 122.56,24.77 E21.3 121.92,24.13 121.92,23.5 v120.65,22.23 120.65,15.88 116.2,15.88 115.57,16.51 115.57,30.48 116.84,31.75 E22.12
  Bottom 0.254: v93.98,20.95 95.25,22.23 v120.65,22.23
N$32  (via drill 0.61)
  Top 0.254: v165.1,67.94 165.1,66.04 E15.8
  Bottom 0.254: v165.1,67.94 127,67.94 125.73,66.67 113.03,66.67 113.03,62.23 113.67,61.59 117.47,61.59 118.75,62.87 E24.12
N$33
  Bottom 0.254: IC6.6 81.92,47.62 83.19,46.35 117.47,46.35 118.75,47.62 E23.13
N$34
  Top 0.254: E40.1 25.4,100.33 25.4,100.97 PAD18.1
N$35
  Bottom 0.254: E5.11 226.69,64.14 233.04,70.48 E5.1
N$36  (via drill 0.61)
  Top 0.254: v212.72,88.27 212.72,89.53 213.36,90.17 213.36,104.14 212.72,104.78 v212.72,106.05 | v153.67,104.78 152.4,106.05 151.76,106.05 148.59,102.87 148.59,100.33 147.96,99.69 146.05,99.69 146.05,109.86 v144.78,111.12 | v116.84,111.12 116.84,109.86 111.12,104.14 111.12,103.5 110.49,102.87 110.49,100.33 109.22,99.06 109.22,95.25 E26.8
  Bottom 0.254: v212.72,88.27 222.88,88.27 223.52,87.63 IC11.5 | v212.72,106.05 212.09,105.41 182.88,105.41 181.61,106.68 160.02,106.68 158.12,104.78 v153.67,104.78 | v144.78,111.12 144.15,111.76 117.47,111.76 v116.84,111.12
N$37  (via drill 0.61)
  Top 0.254: E8.13 205.74,64.77 203.2,67.31 203.2,69.85 E8.3 | v175.26,67.31 175.26,71.12 E15.3
  Bottom 0.254: v175.26,67.31 200.03,67.31 201.93,65.41 203.84,65.41 205.1,64.14 E8.13
N$38
  Bottom 0.254: E8.11 201.29,62.87 202.56,62.87 E8.12
N$39
  Top 0.254: E8.9 195.58,64.77 195.58,69.85 E8.6
N$40
  Bottom 0.254: E8.10 197.49,62.87 196.22,61.59 178.44,61.59 177.16,62.87 174.62,62.87 173.35,64.14 E15.11
N$41
  Top 0.254: E40.2 22.86,100.33 22.86,100.97 PAD19.1
N$42  (via drill 0.61)
  Top 0.254: E17.12 172.09,94.61 170.81,95.89 165.1,95.89 165.1,95.25 E17.9 | v190.5,86.36 190.5,67.31 193.04,64.77 E8.8
  Bottom 0.254: IC7.7 66.67,93.34 67.94,92.08 163.19,92.08 164.47,93.34 E17.9 | v190.5,86.36 185.42,91.44 175.26,91.44 173.35,93.34 E17.12
N$43
  Top 0.254: E40.3 20.32,100.33 20.32,100.97 PAD28.1
N$44
  Top 0.254: E24.6 111.12,70.48 109.86,69.22 106.68,69.22 106.68,92.71 99.06,100.33 E32.1
N$45
  Top 0.254: E1.11 223.52,8.89 219.71,12.7 219.71,25.4 218.44,26.67 E2.6
N$46  (via drill 0.61)
  Top 0.254: v161.29,65.41 163.19,67.31 163.19,98.42 165.1,100.33 E17.8
  Bottom 0.254: v161.29,65.41 160.66,66.04 152.4,66.04 150.5,64.14 E18.13
N$47
  Top 0.254: E1.10 220.34,6.99 219.07,6.99 E1.9 218.44,8.89 218.44,13.97 E1.6
  Bottom 0.254: E2.1 231.78,27.94 234.31,27.94 235.59,26.67 235.59,10.16 223.52,10.16 221.62,8.26 E1.10
N$48
  Top 0.254: E4.10 218.44,46.99 218.44,52.07 E4.7 | E4.3 227.97,52.7 226.69,52.7 E4.4 226.06,54.61 226.06,57.78 R19.2
  Bottom 0.254: E4.7 219.07,53.98 223.52,58.42 225.43,58.42 R19.2
N$49  (via drill 0.61)
  Top 0.254: v187.96,51.44 187.96,5.08 224.79,5.08 226.06,6.35 E1.12
  Bottom 0.254: v187.96,51.44 184.15,55.24 177.16,55.24 175.26,57.15 E14.4
  Bottom 0.508: E14.5 173.35,57.78 174.62,57.78 E14.4
N$50
  Top 0.254: E40.4 17.78,100.33 17.78,100.97 PAD29.1
N$51
  Top 0.254: E40.5 15.24,100.33 15.24,100.97 PAD30.1
N$52
  Top 0.254: E40.6 12.7,100.33 12.7,100.97 PAD31.1
N$53
  Top 0.254: E40.7 10.16,100.33 10.16,100.97 PAD32.1
N$54
  Top 0.254: E40.8 7.62,100.33 7.62,100.97 PAD33.1
N$55
  Top 0.254: E40.16 25.4,90.17 25.4,89.53 PAD34.1
N$56
  Top 0.254: E40.15 22.86,90.17 22.86,89.53 PAD35.1
N$57
  Top 0.254: E40.14 20.32,90.17 20.32,89.53 PAD36.1
N$58
  Top 0.254: E40.13 17.78,90.17 17.78,89.53 PAD37.1
N$59
  Top 0.254: E40.12 15.24,90.17 15.24,89.53 PAD38.1
N$60  (via drill 0.61)
  Top 0.254: v81.28,29.84 81.28,31.75 IC2.6 | v119.38,29.84 120.65,31.11 120.65,43.18 124.46,46.99 E23.15
  Bottom 0.254: v81.28,29.84 v119.38,29.84
N$61
  Top 0.254: E40.11 12.7,90.17 12.7,89.53 PAD39.1
N$62  (via drill 0.61)
  Top 0.254: v100.33,20.95 100.33,22.86 99.06,24.13 IC4.1
  Bottom 0.254: v100.33,20.95 116.2,20.95 118.75,18.41 E21.13
N$63
  Bottom 0.254: IC3.1 85.72,24.77 80.01,19.05 80.01,15.24 124.46,15.24 125.73,16.51 125.73,19.68 123.83,19.68 122.56,18.41 E21.14
N$64
  Bottom 0.254: IC3.6 81.92,17.14 83.19,15.88 122.56,15.88 123.83,17.14 E21.15
N$65
  Bottom 0.254: IC2.1 87,40.01 89.53,37.47 107.95,37.47 109.22,36.2 121.28,36.2 123.83,33.66 E22.15
N$66  (via drill 0.61)
  Top 0.254: v97.79,31.11 97.79,53.34 99.06,54.61 IC5.1
  Bottom 0.254: v97.79,31.11 117.47,31.11 118.75,32.38 E22.13
N$67  (via drill 0.61)
  Top 0.254: v92.71,36.2 92.71,45.72 93.98,46.99 IC5.6
  Bottom 0.254: v92.71,36.2 93.34,35.56 119.38,35.56 121.28,33.66 E22.14
N$68
  Top 0.254: E40.10 10.16,90.17 10.16,89.53 PAD40.1
N$69
  Top 0.254: E40.9 7.62,90.17 7.62,89.53 PAD41.1
N$70
  Top 0.254: E39.1 233.68,102.87 233.68,103.5 PAD42.1
N$71
  Top 0.254: E39.2 231.14,102.87 231.14,103.5 PAD43.1
N$72
  Top 0.254: E39.3 228.6,102.87 228.6,103.5 PAD44.1
N$73
  Top 0.254: E39.4 226.06,102.87 226.06,103.5 PAD45.1
N$74
  Top 0.254: E39.5 223.52,102.87 223.52,103.5 PAD46.1
N$75
  Top 0.254: E39.6 220.98,102.87 220.98,103.5 PAD47.1
N$76
  Top 0.254: E39.7 218.44,102.87 218.44,103.5 PAD48.1
N$77
  Top 0.254: E39.8 215.9,102.87 215.9,103.5 PAD49.1
N$78
  Top 0.254: E39.16 233.68,92.71 233.68,92.08 PAD50.1
N$79
  Top 0.254: E39.15 231.14,92.71 231.14,92.08 PAD51.1
N$80
  Top 0.254: E39.14 228.6,92.71 228.6,92.08 PAD52.1
N$81
  Top 0.254: E39.13 226.06,92.71 226.06,92.08 PAD53.1
N$82
  Top 0.254: E39.12 223.52,92.71 223.52,92.08 PAD54.1
N$83
  Top 0.254: E39.11 220.98,92.71 220.98,92.08 PAD55.1
N$84
  Top 0.254: E39.10 218.44,92.71 218.44,92.08 PAD56.1
N$85
  Top 0.254: E39.9 215.9,92.71 215.9,92.08 PAD57.1
N$86  (via drill 0.61)
  Top 0.254: v95.25,105.41 95.25,77.47 89.53,71.75 E30.5 | v203.2,107.31 204.47,106.05 204.47,81.28 203.2,80.01 IC10.7
  Bottom 0.254: v95.25,105.41 95.89,104.78 111.12,104.78 113.67,107.31 v203.2,107.31
N$87
  Top 0.254: E32.5 89.53,100.97 90.81,100.97 E32.4 91.44,100.33 91.44,97.79 93.98,95.25 E32.12
N$88
  Bottom 0.254: E20.6 140.34,100.97 141.6,99.69 147.96,99.69 149.22,100.97 E20.2
N$89
  Top 0.254: E20.3 147.32,102.87 157.48,113.03 201.93,113.03 201.93,88.9 203.2,87.63 IC10.2
  Bottom 0.254: IC10.2 203.84,85.72 205.1,85.72 IC10.1
N$90  (via drill 0.61)
  Top 0.254: v154.31,111.12 154.31,112.39 144.78,112.39 138.43,106.05 138.43,88.9 139.7,87.63 E19.6 | v218.44,111.12 224.79,104.78 224.79,88.9 226.06,87.63 IC11.4
  Bottom 0.254: v154.31,111.12 v218.44,111.12
N$91  (via drill 0.61)
  Top 0.254: v182.88,83.19 181.61,81.92 v180.34,81.92 | v161.29,81.92 v161.29,87
  Bottom 0.254: v182.88,83.19 184.15,84.45 198.75,84.45 199.39,83.82 211.46,83.82 212.09,84.45 230.5,84.45 231.14,85.09 IC11.2 | v180.34,81.92 179.07,81.92 178.44,82.55 161.93,82.55 v161.29,81.92 | v161.29,87 160.66,87.63 152.4,87.63 E19.1
N$92
  Top 0.254: E18.3 147.32,72.39 147.32,77.47 E19.14
N$93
